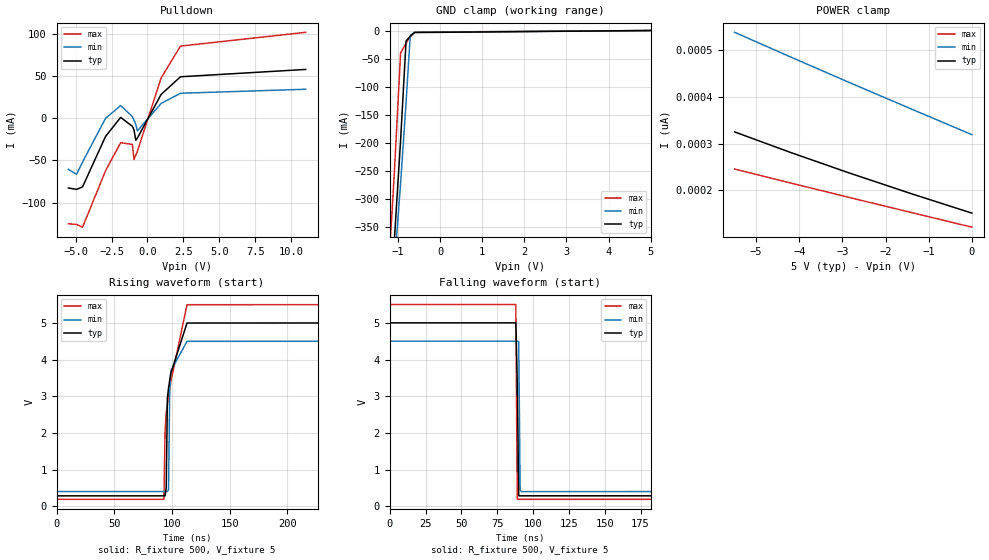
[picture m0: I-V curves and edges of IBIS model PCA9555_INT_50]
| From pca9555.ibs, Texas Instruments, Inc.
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[Model]   PCA9555_INT_50
Model_type  Open_drain
Enable   Active-Low
Vref =   5V
Rref =   1k
Cref =   50p
Vmeas =   2.5
| variable   typ   min   max
C_comp   2.78pF   1.38pF   7.19pF
| C_pulldown   3.12pF   1.58pF   7.49pF
| C_tri-state   2.78pF   1.38pF   7.19pF
[Temperature Range]   40   100   -40
| Ambient temperature   25   85   -40
[Voltage range]   5   4.5   5.5
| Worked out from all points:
|   slope of the pulldown table from 0 to 0.75 V, typ, clamps not added: 32.5 ohm
|   GND clamp passes 1 mA (typ) near -0.53 V on its own axis
|   rising waveform, R_fixture 500, V_fixture 5: 20-80 % time 6.04ns typ, 1.69ns min, 10.9ns max; typ from 0.282 V to 5 V
|   falling waveform, R_fixture 500, V_fixture 5: 20-80 % time 1.12ns typ, 608ps min, 601ps max; typ from 5 V to 0.282 V
[GND Clamp]
| PCA9555_INT_50
|   Voltage   I(typ)   I(min)   I(max)
-5.5V     -2.311A    -2.336A    -2.193A
-1.245V   -538.5mA   -565.8mA   -443.1mA
-1.21V    -503.2mA   -534.5mA   -403.1mA
-1.14V    -429.8mA   -470.1mA   -318.6mA
-1.12V    -408.1mA   -451.2mA   -293.3mA
-1.105V   -391.5mA   -436.9mA   -273.9mA
-1.085V   -369.2mA   -417.7mA   -247.5mA
-940mV    -195.4mA   -271.5mA   -39.9mA
-810mV    -18.59mA   -128.2mA   -22.39mA
-710mV    -10.03mA   -8.507mA   -10.85mA
-605mV    -3.584mA   -3.138mA   -2.905mA
5V        151.6pA    338.8pA    110.5pA
[POWER Clamp]
| PCA9555_INT_50
|   Voltage   I(typ)   I(min)   I(max)
-5.5V     325.2pA    538.1pA    245.8pA
-4.225V   282pA      486.3pA    216.5pA
-2.855V   237.8pA    431.4pA    185.4pA
-1.43V    193.9pA    375.2pA    153.5pA
-95.1fV   151.6pA    319.3pA    121.6pA
[Pulldown]
| PCA9555_INT_50
|   Voltage   I(typ)   I(min)   I(max)
-5.5V     -82.5mA    -60.5mA    -124.8mA
-4.93V    -84.17mA   -66.36mA   -125.6mA
-4.515V   -81.17mA   -51.8mA    -128.8mA
-2.915V   -21.56mA   -126uA     -62.19mA
-1.865V   952uA      14.89mA    -28.91mA
-1.05V    -9.617mA   1.865mA    -31.04mA
-940mV    -13.8mA    -2.129mA   -48.82mA
-810mV    -26.15mA   -7.464mA   -43.65mA
-705mV    -23.57mA   -14.99mA   -39.23mA
950mV     28.07mA    17.41mA    47.58mA
2.295V    48.95mA    29.48mA    85.2mA
11V       57.63mA    34.2mA     101.5mA
[Ramp]
| PCA9555_INT_50
| variable   typ   min   max
dV/dt_r   2.84/6.19E-09   2.46/1.68E-09   3.20/1.07E-08
dV/dt_f   2.84/1.62E-10   2.47/2.88E-10   3.19/8.50E-11
R_load = 500
[Rising Waveform]
| PCA9555_INT_50
R_fixture =   500
C_fixture =   0
L_fixture =   0
V_fixture =   5
V_fixture_min = 4.5
V_fixture_max = 5.5
|   Time   V(typ)   V(min)   V(max)
0s        282.3mV    400mV      187mV
93ns      282.3mV    400mV      187mV
94ns      282.3mV    400mV      2.042V
95ns      510.1mV    400mV      2.548V
96ns      2.957V     400mV      2.766V
97ns      3.227V     447.8mV    2.979V
98ns      3.428V     3.132V     3.189V
99ns      3.624V     3.69V      3.395V
113ns     4.995V     4.496V     5.494V
520ns     5V         4.5V       5.5V
[Falling Waveform]
| PCA9555_INT_50
R_fixture =   500
C_fixture =   0
L_fixture =   0
V_fixture =   5
V_fixture_min = 4.5
V_fixture_max = 5.5
|   Time   V(typ)   V(min)   V(max)
0s        5V         4.5V       5.5V
88ns      5V         4.5V       5.5V
89ns      3.357V     4.5V       194.2mV
90ns      283.5mV    4.483V     187.3mV
91ns      282.3mV    438.2mV    187.5mV
92ns      282.8mV    397.4mV    187.5mV
520ns     282.3mV    400mV      187mV
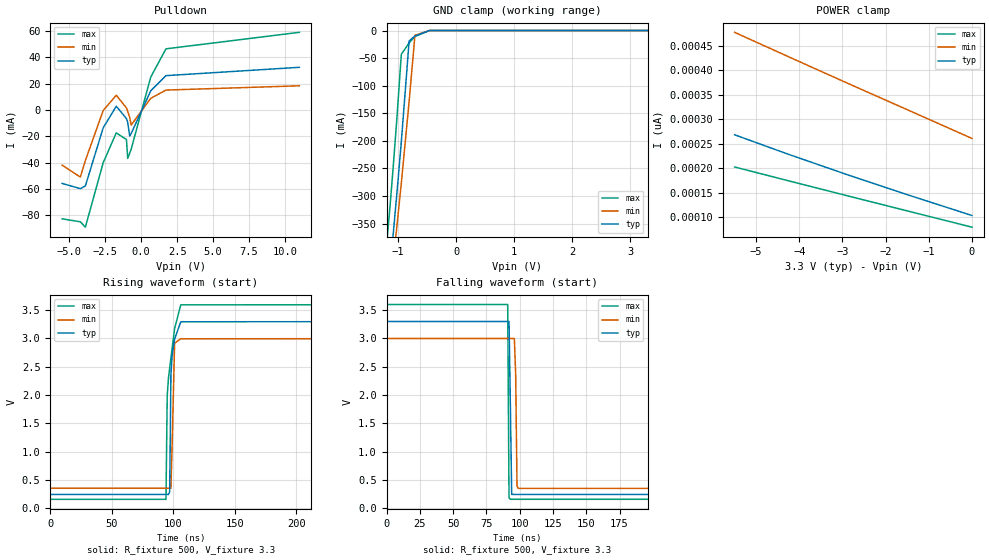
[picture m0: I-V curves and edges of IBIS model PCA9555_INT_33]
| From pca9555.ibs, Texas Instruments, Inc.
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[Model]   PCA9555_INT_33
Model_type  Open_drain
Enable   Active-Low
Vref =   3.3V
Rref =   1k
Cref =   50p
Vmeas =   1.65
| variable   typ   min   max
C_comp   2.00pF   1.33pF   4.90pF
| C_pulldown   2.37pF   1.60pF   5.28pF
| C_tri-state   2.00pF   1.33pF   4.90pF
[Temperature Range]   40   100   -40
| Ambient temperature   25   85   -40
[Voltage range]   3.3   3   3.6
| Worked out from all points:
|   slope of the pulldown table from 0 to 0.495 V, typ, clamps not added: 43.2 ohm
|   GND clamp passes 1 mA (typ) near -0.54 V on its own axis
|   rising waveform, R_fixture 500, V_fixture 3.3: 20-80 % time 1.69ns typ, 1.26ns min, 5.09ns max; typ from 0.247 V to 3.3 V
|   falling waveform, R_fixture 500, V_fixture 3.3: 20-80 % time 1.2ns typ, 920ps min, 605ps max; typ from 3.3 V to 0.247 V
[GND Clamp]
| PCA9555_INT_33
|   Voltage   I(typ)   I(min)   I(max)
-5.5V     -2.311A    -2.336A    -2.193A
-1.25V    -543.5mA   -570.3mA   -448.7mA
-1.215V   -508.3mA   -539mA     -408.9mA
-1.14V    -429.8mA   -470.1mA   -318.6mA
-1.105V   -391.5mA   -436.9mA   -273.9mA
-1.085V   -369.2mA   -417.7mA   -247.5mA
-1.02V    -294.1mA   -353.7mA   -157.3mA
-945mV    -201.8mA   -276.7mA   -43.17mA
-810mV    -18.59mA   -128.2mA   -22.39mA
-710mV    -10.03mA   -8.507mA   -10.85mA
-460mV    -11.77uA   -24uA      -3.816uA
3.3V      103.3pA    272.4pA    72.85pA
[POWER Clamp]
| PCA9555_INT_33
|   Voltage   I(typ)   I(min)   I(max)
-5.5V     268pA      477.2pA    202.3pA
-4.255V   228.3pA    427.5pA    174.2pA
-2.85V    185.4pA    372pA      142.7pA
-1.495V   145.7pA    319.1pA    112.6pA
-95.1fV   103.3pA    260.7pA    79.48pA
[Pulldown]
| PCA9555_INT_33
|   Voltage   I(typ)   I(min)   I(max)
-5.5V     -55.66mA   -41.8mA    -82.53mA
-4.235V   -59.62mA   -50.82mA   -84.8mA
-3.885V   -57.6mA    -38.33mA   -88.86mA
-2.645V   -13.45mA   -303uA     -39.97mA
-1.735V   2.912mA    11.31mA    -17.29mA
-1.025V   -6.471mA   1.566mA    -22.36mA
-940mV    -9.316mA   -951.2uA   -36.66mA
-800mV    -19.64mA   -5.585mA   -32.75mA
-700mV    -17.83mA   -11.37mA   -29.7mA
660mV     14.6mA     8.915mA    25.01mA
1.72V     26.15mA    15.19mA    46.49mA
11V       32.48mA    18.44mA    59.03mA
[Ramp]
| PCA9555_INT_33
| variable   typ   min   max
dV/dt_r   1.83/1.72E-09   1.59/9.99E-10   2.07/4.95E-09
dV/dt_f   1.84/2.36E-10   1.60/4.48E-10   2.06/1.21E-10
R_load = 500
[Rising Waveform]
| PCA9555_INT_33
R_fixture =   500
C_fixture =   0
L_fixture =   0
V_fixture =   3.3
V_fixture_min = 3
V_fixture_max = 3.6
|   Time   V(typ)   V(min)   V(max)
0s        247.1mV    356.9mV    161.2mV
94ns      247.1mV    356.9mV    161.1mV
95ns      247.1mV    356.9mV    1.995V
96ns      247mV      356.9mV    2.296V
97ns      292.8mV    356.9mV    2.479V
98ns      2.359V     355.8mV    2.659V
99ns      2.702V     1.134V     2.833V
101ns     2.989V     2.917V     3.175V
106ns     3.295V     2.995V     3.594V
520ns     3.3V       3V         3.6V
[Falling Waveform]
| PCA9555_INT_33
R_fixture =   500
C_fixture =   0
L_fixture =   0
V_fixture =   3.3
V_fixture_min = 3
V_fixture_max = 3.6
|   Time   V(typ)   V(min)   V(max)
0s        3.3V       3V         3.6V
91ns      3.3V       3V         3.6V
92ns      3.3V       3V         189.3mV
93ns      1.827V     3V         161mV
94ns      248.6mV    3V         161.6mV
96ns      247.5mV    2.999V     161.5mV
97ns      247.5mV    2.362V     161.5mV
98ns      247.5mV    390.1mV    161.5mV
99ns      247.4mV    354mV      161.5mV
520ns     247.1mV    356.9mV    161.2mV
